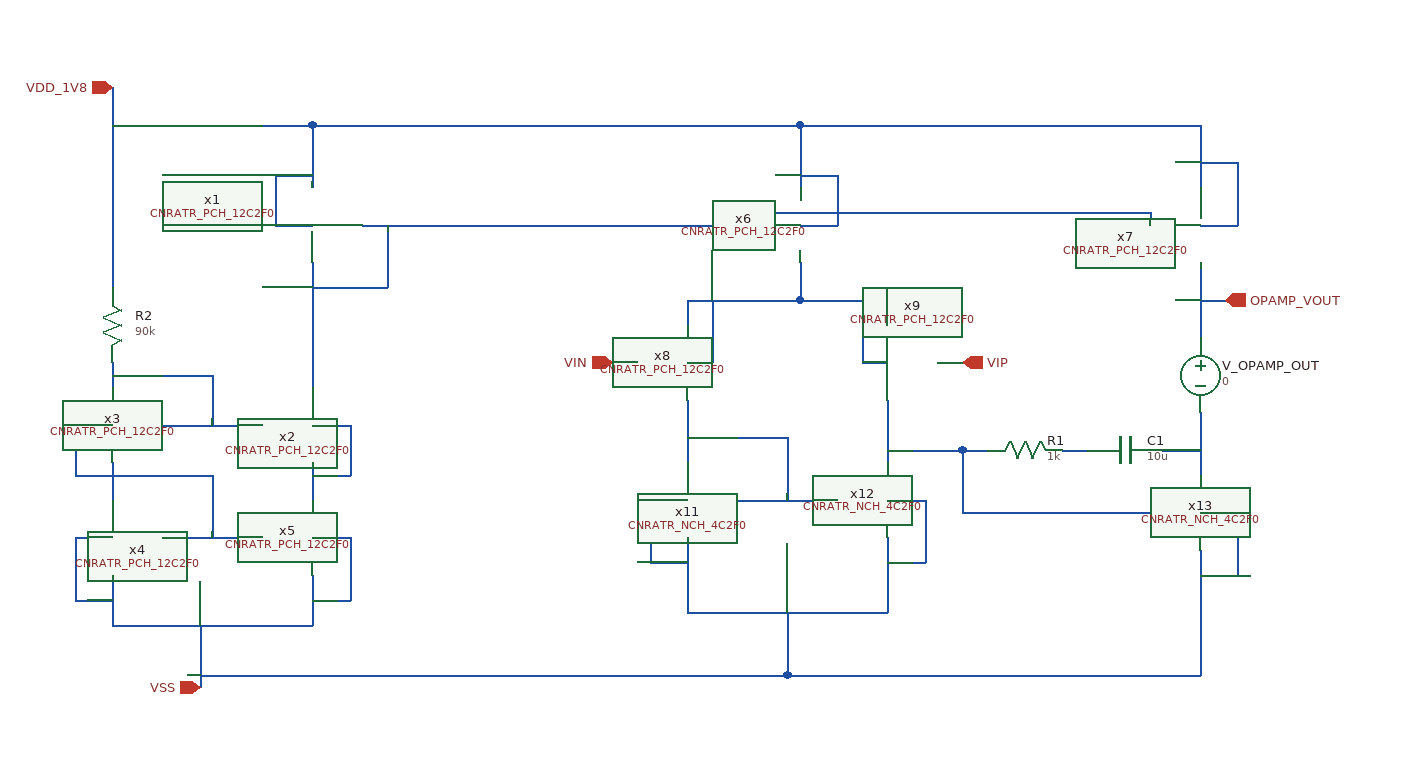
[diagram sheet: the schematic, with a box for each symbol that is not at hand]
v {xschem version=3.4.4 file_version=1.2
}
G {}
K {}
V {}
S {}
E {}
N 260 -550 260 -510 {
lab=VDD_1V8}
N 260 -330 260 -310 {
lab=#net1}
N 260 -250 260 -220 {
lab=#net2}
N 230 -280 260 -280 {
lab=#net2}
N 230 -280 230 -240 {
lab=#net2}
N 230 -240 260 -240 {
lab=#net2}
N 260 -160 260 -120 {
lab=VSS}
N 260 -120 420 -120 {
lab=VSS}
N 420 -160 420 -120 {
lab=VSS}
N 230 -190 260 -190 {
lab=VSS}
N 230 -190 230 -140 {
lab=VSS}
N 230 -140 260 -140 {
lab=VSS}
N 420 -190 450 -190 {
lab=VSS}
N 450 -190 450 -140 {
lab=VSS}
N 420 -140 450 -140 {
lab=VSS}
N 420 -250 420 -220 {
lab=#net3}
N 420 -280 450 -280 {
lab=#net3}
N 450 -280 450 -240 {
lab=#net3}
N 420 -240 450 -240 {
lab=#net3}
N 300 -280 380 -280 {
lab=#net1}
N 300 -190 380 -190 {
lab=#net2}
N 260 -240 340 -240 {
lab=#net2}
N 340 -240 340 -190 {
lab=#net2}
N 260 -320 340 -320 {
lab=#net1}
N 340 -320 340 -280 {
lab=#net1}
N 330 -120 330 -70 {
lab=VSS}
N 420 -370 420 -310 {
lab=#net4}
N 370 -520 420 -520 {
lab=VDD_1V8}
N 420 -520 420 -470 {
lab=VDD_1V8}
N 390 -440 420 -440 {
lab=VDD_1V8}
N 390 -480 390 -440 {
lab=VDD_1V8}
N 390 -480 420 -480 {
lab=VDD_1V8}
N 420 -410 420 -370 {
lab=#net4}
N 460 -440 770 -440 {
lab=#net4}
N 420 -520 810 -520 {
lab=VDD_1V8}
N 810 -520 810 -470 {
lab=VDD_1V8}
N 1130 -520 1130 -470 {
lab=VDD_1V8}
N 770 -450 770 -440 {
lab=#net4}
N 770 -450 1090 -450 {
lab=#net4}
N 1090 -450 1090 -440 {
lab=#net4}
N 260 -520 370 -520 {
lab=VDD_1V8}
N 810 -410 810 -380 {
lab=#net5}
N 810 -380 880 -380 {
lab=#net5}
N 880 -380 880 -360 {
lab=#net5}
N 720 -380 810 -380 {
lab=#net5}
N 720 -380 720 -360 {
lab=#net5}
N 860 -330 880 -330 {
lab=#net5}
N 860 -380 860 -330 {
lab=#net5}
N 720 -330 740 -330 {
lab=#net5}
N 740 -380 740 -330 {
lab=#net5}
N 920 -330 940 -330 {
lab=VIP}
N 660 -330 680 -330 {
lab=VIN}
N 720 -300 720 -250 {
lab=#net6}
N 880 -300 880 -250 {
lab=#net7}
N 760 -220 840 -220 {
lab=#net6}
N 720 -270 800 -270 {
lab=#net6}
N 800 -270 800 -220 {
lab=#net6}
N 720 -190 720 -130 {
lab=VSS}
N 720 -130 880 -130 {
lab=VSS}
N 880 -190 880 -130 {
lab=VSS}
N 800 -130 800 -80 {
lab=VSS}
N 880 -220 910 -220 {
lab=VSS}
N 910 -220 910 -170 {
lab=VSS}
N 880 -170 910 -170 {
lab=VSS}
N 690 -220 720 -220 {
lab=VSS}
N 690 -220 690 -170 {
lab=VSS}
N 690 -170 720 -170 {
lab=VSS}
N 1130 -440 1160 -440 {
lab=VDD_1V8}
N 1160 -490 1160 -440 {
lab=VDD_1V8}
N 1130 -490 1160 -490 {
lab=VDD_1V8}
N 810 -440 840 -440 {
lab=VDD_1V8}
N 840 -480 840 -440 {
lab=VDD_1V8}
N 810 -480 840 -480 {
lab=VDD_1V8}
N 940 -260 940 -210 {
lab=#net7}
N 940 -210 1090 -210 {
lab=#net7}
N 1020 -260 1040 -260 {
lab=#net8}
N 1100 -260 1130 -260 {
lab=#net9}
N 1130 -180 1130 -90 {
lab=VSS}
N 1130 -210 1160 -210 {
lab=VSS}
N 1160 -210 1160 -160 {
lab=VSS}
N 1130 -160 1160 -160 {
lab=VSS}
N 1130 -90 1130 -80 {
lab=VSS}
N 800 -80 1130 -80 {
lab=VSS}
N 330 -80 800 -80 {
lab=VSS}
N 1130 -380 1150 -380 {
lab=OPAMP_VOUT}
N 480 -440 480 -390 {
lab=#net4}
N 420 -390 480 -390 {
lab=#net4}
N 260 -510 260 -450 {
lab=VDD_1V8}
N 1130 -410 1130 -350 {
lab=OPAMP_VOUT}
N 1130 -290 1130 -240 {
lab=#net9}
N 810 -520 1130 -520 {
lab=VDD_1V8}
N 260 -450 260 -410 {
lab=VDD_1V8}
N 880 -260 940 -260 {
lab=#net7}
N 940 -260 960 -260 {
lab=#net7}
N 260 -410 260 -390 {
lab=VDD_1V8}
C {devices/ipin.sym} 260 -550 0 0 {name=p1 lab=VDD_1V8}
C {devices/ipin.sym} 330 -70 0 0 {name=p2 lab=VSS}
C {devices/ipin.sym} 660 -330 0 0 {name=p3 lab=VIN}
C {devices/ipin.sym} 940 -330 0 1 {name=p4 lab=VIP}
C {/home/local/syverhar/pro/aicex/ip/cnr_atr_sky130nm/design/CNR_ATR_SKY130NM/CNRATR_NCH_4C2F0.sym} 760 -220 0 1 {name=x11 }
C {/home/local/syverhar/pro/aicex/ip/cnr_atr_sky130nm/design/CNR_ATR_SKY130NM/CNRATR_NCH_4C2F0.sym} 840 -220 0 0 {name=x12 }
C {/home/local/syverhar/pro/aicex/ip/cnr_atr_sky130nm/design/CNR_ATR_SKY130NM/CNRATR_NCH_4C2F0.sym} 1090 -210 0 0 {name=x13 }
C {devices/capa.sym} 1070 -260 3 0 {name=C1
m=1
value=10u
footprint=1206
device="ceramic capacitor"}
C {devices/opin.sym} 1150 -380 0 0 {name=p5 lab=OPAMP_VOUT}
C {/home/local/syverhar/pro/aicex/ip/cnr_atr_sky130nm/design/CNR_ATR_SKY130NM/CNRATR_PCH_12C2F0.sym} 460 -440 0 1 {name=x1 }
C {/home/local/syverhar/pro/aicex/ip/cnr_atr_sky130nm/design/CNR_ATR_SKY130NM/CNRATR_PCH_12C2F0.sym} 770 -440 0 0 {name=x6 }
C {/home/local/syverhar/pro/aicex/ip/cnr_atr_sky130nm/design/CNR_ATR_SKY130NM/CNRATR_PCH_12C2F0.sym} 1090 -440 0 0 {name=x7 }
C {/home/local/syverhar/pro/aicex/ip/cnr_atr_sky130nm/design/CNR_ATR_SKY130NM/CNRATR_PCH_12C2F0.sym} 680 -330 0 0 {name=x8 }
C {/home/local/syverhar/pro/aicex/ip/cnr_atr_sky130nm/design/CNR_ATR_SKY130NM/CNRATR_PCH_12C2F0.sym} 920 -330 0 1 {name=x9 }
C {devices/vsource.sym} 1130 -320 0 0 {name=V_OPAMP_OUT value=0 savecurrent=false}
C {/home/local/syverhar/pro/aicex/ip/cnr_atr_sky130nm/design/CNR_ATR_SKY130NM/CNRATR_PCH_12C2F0.sym} 380 -280 0 0 {name=x2 }
C {/home/local/syverhar/pro/aicex/ip/cnr_atr_sky130nm/design/CNR_ATR_SKY130NM/CNRATR_PCH_12C2F0.sym} 300 -280 0 1 {name=x3 }
C {/home/local/syverhar/pro/aicex/ip/cnr_atr_sky130nm/design/CNR_ATR_SKY130NM/CNRATR_PCH_12C2F0.sym} 300 -190 0 1 {name=x4 }
C {/home/local/syverhar/pro/aicex/ip/cnr_atr_sky130nm/design/CNR_ATR_SKY130NM/CNRATR_PCH_12C2F0.sym} 380 -190 0 0 {name=x5 }
C {devices/res.sym} 990 -260 3 0 {name=R1
value=1k
footprint=1206
device=resistor
m=1}
C {devices/res.sym} 260 -360 0 0 {name=R2
value=90k
footprint=1206
device=resistor
m=1}
